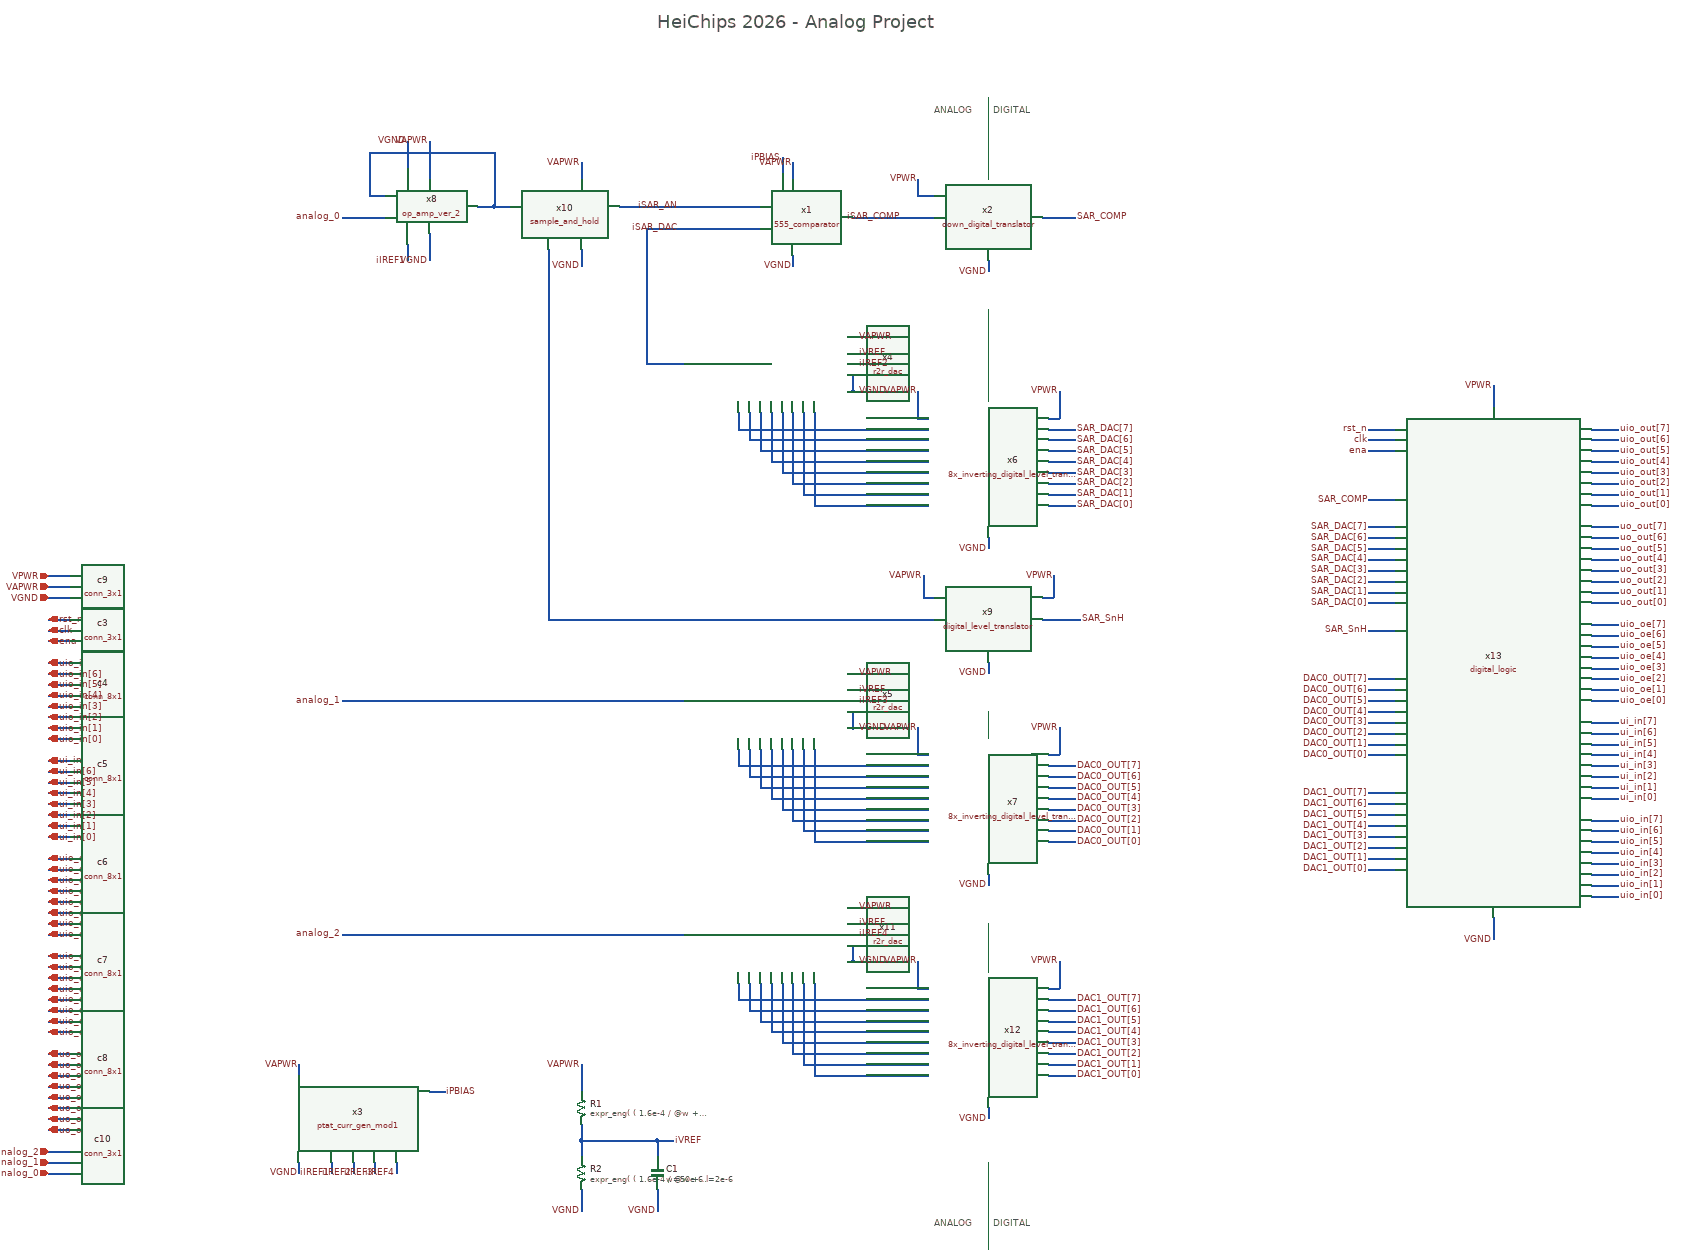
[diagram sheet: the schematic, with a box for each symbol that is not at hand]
v {xschem version=3.4.8RC file_version=1.3}
G {}
K {}
V {}
S {}
F {}
E {}
L 4 1890 -2240 1890 -2090 {fill = false
dash = 16}
L 4 1890 -1850 1890 -1680 {fill = false
dash = 16}
L 4 1890 -1110 1890 -1060 {fill = false
dash = 16}
L 4 1890 -720 1890 -630 {fill = false
dash = 16}
L 4 1890 -280 1890 -30 {fill = false
dash = 16}
T {HeiChips 2026 - Analog Project} 1280 -2390 0 0 1 1 {}
T {ANALOG} 1790 -2230 0 0 0.4 0.4 {}
T {DIGITAL} 1900 -2230 0 0 0.4 0.4 {}
T {ANALOG} 1790 -180 0 0 0.4 0.4 {}
T {DIGITAL} 1900 -180 0 0 0.4 0.4 {}
N 620 -460 620 -440 {lab=VAPWR}
N 1530 -2120 1530 -2090 {lab=VAPWR}
N 620 -280 620 -260 {lab=VGND}
N 1530 -1950 1530 -1930 {lab=VGND}
N 1890 -1940 1890 -1920 {lab=VGND}
N 1760 -2060 1790 -2060 {lab=VPWR}
N 1760 -2090 1760 -2060 {lab=VPWR}
N 2020 -1700 2020 -1650 {lab=VPWR}
N 2000 -1650 2020 -1650 {lab=VPWR}
N 2020 -1080 2020 -1030 {lab=VPWR}
N 2000 -1030 2020 -1030 {lab=VPWR}
N 1760 -1650 1780 -1650 {lab=VAPWR}
N 1760 -1700 1760 -1650 {lab=VAPWR}
N 1760 -1030 1780 -1030 {lab=VAPWR}
N 1760 -1080 1760 -1030 {lab=VAPWR}
N 1890 -810 1890 -790 {lab=VGND}
N 1890 -1430 1890 -1410 {lab=VGND}
N 1430 -1630 1780 -1630 {lab=#net1}
N 1430 -1660 1430 -1630 {lab=#net1}
N 1450 -1610 1780 -1610 {lab=#net2}
N 1450 -1660 1450 -1610 {lab=#net2}
N 1470 -1590 1780 -1590 {lab=#net3}
N 1470 -1660 1470 -1590 {lab=#net3}
N 1490 -1570 1780 -1570 {lab=#net4}
N 1490 -1660 1490 -1570 {lab=#net4}
N 1510 -1550 1780 -1550 {lab=#net5}
N 1510 -1660 1510 -1550 {lab=#net5}
N 1530 -1530 1780 -1530 {lab=#net6}
N 1530 -1660 1530 -1530 {lab=#net6}
N 1550 -1510 1780 -1510 {lab=#net7}
N 1550 -1660 1550 -1510 {lab=#net7}
N 1570 -1490 1780 -1490 {lab=#net8}
N 1570 -1660 1570 -1490 {lab=#net8}
N 1430 -1010 1780 -1010 {lab=#net9}
N 1430 -1040 1430 -1010 {lab=#net9}
N 1450 -990 1780 -990 {lab=#net10}
N 1450 -1040 1450 -990 {lab=#net10}
N 1470 -970 1780 -970 {lab=#net11}
N 1470 -1040 1470 -970 {lab=#net11}
N 1490 -950 1780 -950 {lab=#net12}
N 1490 -1040 1490 -950 {lab=#net12}
N 1510 -930 1780 -930 {lab=#net13}
N 1510 -1040 1510 -930 {lab=#net13}
N 1550 -890 1780 -890 {lab=#net14}
N 1550 -1040 1550 -890 {lab=#net14}
N 1530 -910 1780 -910 {lab=#net15}
N 1530 -1040 1530 -910 {lab=#net15}
N 1570 -870 1780 -870 {lab=#net16}
N 1570 -1040 1570 -870 {lab=#net16}
N 1640 -1700 1650 -1700 {lab=VGND}
N 1640 -1080 1650 -1080 {lab=VGND}
N 1630 -1180 1650 -1180 {lab=VAPWR}
N 1630 -1800 1650 -1800 {lab=VAPWR}
N 1630 -1730 1640 -1730 {lab=VGND}
N 1640 -1730 1640 -1700 {lab=VGND}
N 1630 -1700 1640 -1700 {lab=VGND}
N 1630 -1110 1640 -1110 {lab=VGND}
N 1640 -1110 1640 -1080 {lab=VGND}
N 1630 -1080 1640 -1080 {lab=VGND}
N 1640 -2020 1790 -2020 {lab=iSAR_COMP}
N 1260 -2000 1470 -2000 {lab=iSAR_DAC}
N 1260 -2000 1260 -1750 {lab=iSAR_DAC}
N 1260 -1750 1330 -1750 {lab=iSAR_DAC}
N 750 -2060 780 -2060 {lab=#net17}
N 750 -2140 750 -2060 {lab=#net17}
N 750 -2140 980 -2140 {lab=#net17}
N 950 -2040 980 -2040 {lab=#net17}
N 980 -2140 980 -2040 {lab=#net17}
N 860 -1990 860 -1940 {lab=VGND}
N 860 -2160 860 -2090 {lab=VAPWR}
N 820 -2160 820 -2110 {lab=VGND}
N 760 -280 760 -260 {lab=iIREF3}
N 720 -280 720 -260 {lab=iIREF2}
N 680 -280 680 -260 {lab=iIREF1}
N 1630 -1130 1650 -1130 {lab=iIREF3}
N 1630 -1750 1650 -1750 {lab=iIREF2}
N 820 -1970 820 -1940 {lab=iIREF1}
N 1140 -350 1140 -320 {lab=iVREF}
N 1140 -320 1280 -320 {lab=iVREF}
N 1280 -320 1280 -290 {lab=iVREF}
N 1140 -320 1140 -290 {lab=iVREF}
N 1280 -320 1310 -320 {lab=iVREF}
N 1140 -460 1140 -410 {lab=VAPWR}
N 1140 -230 1140 -190 {lab=VGND}
N 1630 -1770 1650 -1770 {lab=iVREF}
N 1630 -1150 1650 -1150 {lab=iVREF}
N 700 -2020 780 -2020 {lab=analog_0}
N 860 -410 890 -410 {lab=iPBIAS}
N 1510 -2130 1510 -2100 {lab=iPBIAS}
N 1770 -1320 1790 -1320 {lab=VAPWR}
N 1770 -1360 1770 -1320 {lab=VAPWR}
N 1990 -1320 2010 -1320 {lab=VPWR}
N 2010 -1360 2010 -1320 {lab=VPWR}
N 1890 -1200 1890 -1180 {lab=VGND}
N 1080 -1280 1790 -1280 {lab=#net18}
N 2000 -870 2050 -870 {lab=DAC0_OUT[0]}
N 2000 -890 2050 -890 {lab=DAC0_OUT[1]}
N 2000 -910 2050 -910 {lab=DAC0_OUT[2]}
N 2000 -930 2050 -930 {lab=DAC0_OUT[3]}
N 2000 -970 2050 -970 {lab=DAC0_OUT[5]}
N 2000 -950 2050 -950 {lab=DAC0_OUT[4]}
N 2000 -990 2050 -990 {lab=DAC0_OUT[6]}
N 2000 -1010 2050 -1010 {lab=DAC0_OUT[7]}
N 2000 -1490 2050 -1490 {lab=SAR_DAC[0]}
N 2000 -1510 2050 -1510 {lab=SAR_DAC[1]}
N 2000 -1530 2050 -1530 {lab=SAR_DAC[2]}
N 2000 -1550 2050 -1550 {lab=SAR_DAC[3]}
N 2000 -1570 2050 -1570 {lab=SAR_DAC[4]}
N 2000 -1590 2050 -1590 {lab=SAR_DAC[5]}
N 2000 -1610 2050 -1610 {lab=SAR_DAC[6]}
N 2000 -1630 2050 -1630 {lab=SAR_DAC[7]}
N 1990 -2020 2050 -2020 {lab=SAR_COMP}
N 1990 -1280 2060 -1280 {lab=SAR_SnH}
N 1280 -230 1280 -190 {lab=VGND}
N 160 -1260 200 -1260 {lab=clk}
N 160 -1240 200 -1240 {lab=ena}
N 160 -1280 200 -1280 {lab=rst_n}
N 160 -1200 200 -1200 {lab=uio_in[7]}
N 160 -1180 200 -1180 {lab=uio_in[6]}
N 160 -1160 200 -1160 {lab=uio_in[5]}
N 160 -1140 200 -1140 {lab=uio_in[4]}
N 160 -1120 200 -1120 {lab=uio_in[3]}
N 160 -1100 200 -1100 {lab=uio_in[2]}
N 160 -1080 200 -1080 {lab=uio_in[1]}
N 160 -1060 200 -1060 {lab=uio_in[0]}
N 160 -1020 200 -1020 {lab=ui_in[7]}
N 160 -1000 200 -1000 {lab=ui_in[6]}
N 160 -980 200 -980 {lab=ui_in[5]}
N 160 -960 200 -960 {lab=ui_in[4]}
N 160 -940 200 -940 {lab=ui_in[3]}
N 160 -920 200 -920 {lab=ui_in[2]}
N 160 -900 200 -900 {lab=ui_in[1]}
N 160 -880 200 -880 {lab=ui_in[0]}
N 160 -840 200 -840 {lab=uio_oe[7]}
N 160 -820 200 -820 {lab=uio_oe[6]}
N 160 -800 200 -800 {lab=uio_oe[5]}
N 160 -780 200 -780 {lab=uio_oe[4]}
N 160 -760 200 -760 {lab=uio_oe[3]}
N 160 -740 200 -740 {lab=uio_oe[2]}
N 160 -720 200 -720 {lab=uio_oe[1]}
N 160 -700 200 -700 {lab=uio_oe[0]}
N 160 -660 200 -660 {lab=uio_out[7]}
N 160 -640 200 -640 {lab=uio_out[6]}
N 160 -620 200 -620 {lab=uio_out[5]}
N 160 -600 200 -600 {lab=uio_out[4]}
N 160 -580 200 -580 {lab=uio_out[3]}
N 160 -560 200 -560 {lab=uio_out[2]}
N 160 -540 200 -540 {lab=uio_out[1]}
N 160 -520 200 -520 {lab=uio_out[0]}
N 160 -480 200 -480 {lab=uo_out[7]}
N 160 -460 200 -460 {lab=uo_out[6]}
N 160 -440 200 -440 {lab=uo_out[5]}
N 160 -420 200 -420 {lab=uo_out[4]}
N 160 -400 200 -400 {lab=uo_out[3]}
N 160 -380 200 -380 {lab=uo_out[2]}
N 160 -360 200 -360 {lab=uo_out[1]}
N 160 -340 200 -340 {lab=uo_out[0]}
N 160 -1340 200 -1340 {lab=VAPWR}
N 160 -1320 200 -1320 {lab=VGND}
N 160 -1360 200 -1360 {lab=VPWR}
N 160 -300 200 -300 {lab=analog_2}
N 160 -280 200 -280 {lab=analog_1}
N 160 -260 200 -260 {lab=analog_0}
N 980 -2040 1010 -2040 {lab=#net17}
N 1210 -2040 1470 -2040 {lab=iSAR_AN}
N 1080 -1960 1080 -1280 {lab=#net18}
N 1140 -1960 1140 -1930 {lab=VGND}
N 1140 -2120 1140 -2090 {lab=VAPWR}
N 2020 -650 2020 -600 {lab=VPWR}
N 2000 -600 2020 -600 {lab=VPWR}
N 1760 -600 1780 -600 {lab=VAPWR}
N 1760 -650 1760 -600 {lab=VAPWR}
N 1890 -380 1890 -360 {lab=VGND}
N 1430 -580 1780 -580 {lab=#net19}
N 1430 -610 1430 -580 {lab=#net19}
N 1450 -560 1780 -560 {lab=#net20}
N 1450 -610 1450 -560 {lab=#net20}
N 1470 -540 1780 -540 {lab=#net21}
N 1470 -610 1470 -540 {lab=#net21}
N 1490 -520 1780 -520 {lab=#net22}
N 1490 -610 1490 -520 {lab=#net22}
N 1510 -500 1780 -500 {lab=#net23}
N 1510 -610 1510 -500 {lab=#net23}
N 1550 -460 1780 -460 {lab=#net24}
N 1550 -610 1550 -460 {lab=#net24}
N 1530 -480 1780 -480 {lab=#net25}
N 1530 -610 1530 -480 {lab=#net25}
N 1570 -440 1780 -440 {lab=#net26}
N 1570 -610 1570 -440 {lab=#net26}
N 1640 -650 1650 -650 {lab=VGND}
N 1630 -750 1650 -750 {lab=VAPWR}
N 1630 -680 1640 -680 {lab=VGND}
N 1640 -680 1640 -650 {lab=VGND}
N 1630 -650 1640 -650 {lab=VGND}
N 1630 -700 1650 -700 {lab=iIREF4}
N 1630 -720 1650 -720 {lab=iVREF}
N 800 -280 800 -260 {lab=iIREF3}
N 700 -700 1330 -700 {lab=analog_2}
N 700 -1130 1330 -1130 {lab=analog_1}
N 2000 -440 2050 -440 {lab=DAC1_OUT[0]}
N 2000 -460 2050 -460 {lab=DAC1_OUT[1]}
N 2000 -480 2050 -480 {lab=DAC1_OUT[2]}
N 2000 -500 2050 -500 {lab=DAC1_OUT[3]}
N 2000 -540 2050 -540 {lab=DAC1_OUT[5]}
N 2000 -520 2050 -520 {lab=DAC1_OUT[4]}
N 2000 -560 2050 -560 {lab=DAC1_OUT[6]}
N 2000 -580 2050 -580 {lab=DAC1_OUT[7]}
N 2590 -820 2640 -820 {lab=DAC1_OUT[0]}
N 2590 -840 2640 -840 {lab=DAC1_OUT[1]}
N 2590 -860 2640 -860 {lab=DAC1_OUT[2]}
N 2590 -880 2640 -880 {lab=DAC1_OUT[3]}
N 2590 -920 2640 -920 {lab=DAC1_OUT[5]}
N 2590 -900 2640 -900 {lab=DAC1_OUT[4]}
N 2590 -940 2640 -940 {lab=DAC1_OUT[6]}
N 2590 -960 2640 -960 {lab=DAC1_OUT[7]}
N 2590 -1030 2640 -1030 {lab=DAC0_OUT[0]}
N 2590 -1050 2640 -1050 {lab=DAC0_OUT[1]}
N 2590 -1070 2640 -1070 {lab=DAC0_OUT[2]}
N 2590 -1090 2640 -1090 {lab=DAC0_OUT[3]}
N 2590 -1130 2640 -1130 {lab=DAC0_OUT[5]}
N 2590 -1110 2640 -1110 {lab=DAC0_OUT[4]}
N 2590 -1150 2640 -1150 {lab=DAC0_OUT[6]}
N 2590 -1170 2640 -1170 {lab=DAC0_OUT[7]}
N 2590 -1260 2640 -1260 {lab=SAR_SnH}
N 2590 -1310 2640 -1310 {lab=SAR_DAC[0]}
N 2590 -1330 2640 -1330 {lab=SAR_DAC[1]}
N 2590 -1350 2640 -1350 {lab=SAR_DAC[2]}
N 2590 -1370 2640 -1370 {lab=SAR_DAC[3]}
N 2590 -1390 2640 -1390 {lab=SAR_DAC[4]}
N 2590 -1410 2640 -1410 {lab=SAR_DAC[5]}
N 2590 -1430 2640 -1430 {lab=SAR_DAC[6]}
N 2590 -1450 2640 -1450 {lab=SAR_DAC[7]}
N 2590 -1500 2640 -1500 {lab=SAR_COMP}
N 2590 -1630 2640 -1630 {lab=rst_n}
N 2590 -1610 2640 -1610 {lab=clk}
N 2590 -1590 2640 -1590 {lab=ena}
N 2820 -730 2820 -690 {lab=VGND}
N 2820 -1710 2820 -1670 {lab=VPWR}
N 3000 -1490 3050 -1490 {lab=SAR_DAC[0]}
N 3000 -1510 3050 -1510 {lab=SAR_DAC[1]}
N 3000 -1530 3050 -1530 {lab=SAR_DAC[2]}
N 3000 -1550 3050 -1550 {lab=SAR_DAC[3]}
N 3000 -1570 3050 -1570 {lab=SAR_DAC[4]}
N 3000 -1590 3050 -1590 {lab=SAR_DAC[5]}
N 3000 -1610 3050 -1610 {lab=SAR_DAC[6]}
N 3000 -1630 3050 -1630 {lab=SAR_DAC[7]}
N 3000 -1310 3050 -1310 {lab=SAR_DAC[0]}
N 3000 -1330 3050 -1330 {lab=SAR_DAC[1]}
N 3000 -1350 3050 -1350 {lab=SAR_DAC[2]}
N 3000 -1370 3050 -1370 {lab=SAR_DAC[3]}
N 3000 -1390 3050 -1390 {lab=SAR_DAC[4]}
N 3000 -1410 3050 -1410 {lab=SAR_DAC[5]}
N 3000 -1430 3050 -1430 {lab=SAR_DAC[6]}
N 3000 -1450 3050 -1450 {lab=SAR_DAC[7]}
N 3000 -1130 3050 -1130 {lab=SAR_DAC[0]}
N 3000 -1150 3050 -1150 {lab=SAR_DAC[1]}
N 3000 -1170 3050 -1170 {lab=SAR_DAC[2]}
N 3000 -1190 3050 -1190 {lab=SAR_DAC[3]}
N 3000 -1210 3050 -1210 {lab=SAR_DAC[4]}
N 3000 -1230 3050 -1230 {lab=SAR_DAC[5]}
N 3000 -1250 3050 -1250 {lab=SAR_DAC[6]}
N 3000 -1270 3050 -1270 {lab=SAR_DAC[7]}
N 3000 -950 3050 -950 {lab=SAR_DAC[0]}
N 3000 -970 3050 -970 {lab=SAR_DAC[1]}
N 3000 -990 3050 -990 {lab=SAR_DAC[2]}
N 3000 -1010 3050 -1010 {lab=SAR_DAC[3]}
N 3000 -1030 3050 -1030 {lab=SAR_DAC[4]}
N 3000 -1050 3050 -1050 {lab=SAR_DAC[5]}
N 3000 -1070 3050 -1070 {lab=SAR_DAC[6]}
N 3000 -1090 3050 -1090 {lab=SAR_DAC[7]}
N 3000 -770 3050 -770 {lab=SAR_DAC[0]}
N 3000 -790 3050 -790 {lab=SAR_DAC[1]}
N 3000 -810 3050 -810 {lab=SAR_DAC[2]}
N 3000 -830 3050 -830 {lab=SAR_DAC[3]}
N 3000 -850 3050 -850 {lab=SAR_DAC[4]}
N 3000 -870 3050 -870 {lab=SAR_DAC[5]}
N 3000 -890 3050 -890 {lab=SAR_DAC[6]}
N 3000 -910 3050 -910 {lab=SAR_DAC[7]}
C {title-2.sym} 0 0 0 0 {name=l1 author="B. L., G. B., T. M., P. G." rev=1.0 lock=true}
C {555_comparator.sym} 1490 -2020 0 0 {name=x1}
C {down_digital_translator.sym} 1810 -1960 0 0 {name=x2}
C {ptat_curr_gen_mod1.sym} 590 -300 0 0 {name=x3}
C {r2r_dac.sym} 1690 -1590 0 1 {name=x4}
C {r2r_dac.sym} 1690 -970 0 1 {name=x5}
C {8x_inverting_digital_level_translator.sym} 1980 -1450 0 1 {name=x6}
C {8x_inverting_digital_level_translator.sym} 1980 -830 0 1 {name=x7}
C {lab_pin.sym} 620 -460 1 0 {name=p1 sig_type=std_logic lab=VAPWR
}
C {lab_pin.sym} 1530 -2120 1 0 {name=p2 sig_type=std_logic lab=VAPWR
}
C {lab_pin.sym} 620 -260 3 0 {name=p5 sig_type=std_logic lab=VGND
}
C {lab_pin.sym} 1530 -1930 3 0 {name=p6 sig_type=std_logic lab=VGND
}
C {lab_pin.sym} 1890 -1920 3 0 {name=p7 sig_type=std_logic lab=VGND
}
C {lab_pin.sym} 1760 -2090 1 0 {name=p10 sig_type=std_logic lab=VPWR
}
C {lab_pin.sym} 2020 -1700 1 0 {name=p11 sig_type=std_logic lab=VPWR
}
C {lab_pin.sym} 2020 -1080 1 0 {name=p19 sig_type=std_logic lab=VPWR
}
C {lab_pin.sym} 1760 -1700 1 0 {name=p20 sig_type=std_logic lab=VAPWR
}
C {lab_pin.sym} 1760 -1080 1 0 {name=p21 sig_type=std_logic lab=VAPWR
}
C {lab_pin.sym} 1890 -1410 3 0 {name=p22 sig_type=std_logic lab=VGND
}
C {lab_pin.sym} 1890 -790 3 0 {name=p23 sig_type=std_logic lab=VGND
}
C {lab_pin.sym} 1650 -1800 2 0 {name=p24 sig_type=std_logic lab=VAPWR
}
C {lab_pin.sym} 1650 -1180 2 0 {name=p67 sig_type=std_logic lab=VAPWR
}
C {lab_pin.sym} 1650 -1080 2 0 {name=p68 sig_type=std_logic lab=VGND
}
C {lab_pin.sym} 1650 -1700 2 0 {name=p69 sig_type=std_logic lab=VGND
}
C {lab_pin.sym} 890 -410 2 0 {name=p70 sig_type=std_logic lab=iPBIAS
}
C {op_amp_ver_2.sym} 850 -2040 0 0 {name=x8}
C {lab_pin.sym} 860 -2160 1 0 {name=p71 sig_type=std_logic lab=VAPWR
}
C {lab_pin.sym} 860 -1940 3 0 {name=p72 sig_type=std_logic lab=VGND
}
C {lab_pin.sym} 820 -2160 1 0 {name=p73 sig_type=std_logic lab=VGND
}
C {lab_pin.sym} 680 -260 3 0 {name=p74 sig_type=std_logic lab=iIREF1
}
C {lab_pin.sym} 720 -260 3 0 {name=p75 sig_type=std_logic lab=iIREF2

}
C {lab_pin.sym} 760 -260 3 0 {name=p76 sig_type=std_logic lab=iIREF3
}
C {lab_pin.sym} 820 -1940 3 0 {name=p77 sig_type=std_logic lab=iIREF1
}
C {lab_pin.sym} 1650 -1750 2 0 {name=p78 sig_type=std_logic lab=iIREF2

}
C {lab_pin.sym} 1650 -1130 2 0 {name=p79 sig_type=std_logic lab=iIREF3
}
C {sg13cmos5l_pr/rhigh.sym} 1140 -380 0 0 {name=R1
w=0.5e-6
l=50e-6
model=rhigh
body=VGND
spiceprefix=X
b=0
 m=1
  mm_ok=1
value="expr_eng(  ( 1.6e-4 / @w + 1360.0 * ( (@b + 1)* @l + ( 1.081*( @w - 0.04e-6 ) + 0.18e-6 )*@b ) / ( @w - 0.04e-6 ) ) / @m  )"
}
C {sg13cmos5l_pr/rhigh.sym} 1140 -260 0 0 {name=R2
w=0.5e-6
l=50e-6
model=rhigh
body=VGND
spiceprefix=X
b=0
 m=1
  mm_ok=1
value="expr_eng(  ( 1.6e-4 / @w + 1360.0 * ( (@b + 1)* @l + ( 1.081*( @w - 0.04e-6 ) + 0.18e-6 )*@b ) / ( @w - 0.04e-6 ) ) / @m  )"
}
C {sg13cmos5l_pr/cap_cmomi.sym} 1280 -260 0 0 {name=C1
model=cap_cmomi
w=50e-6
l=2e-6
mmin=2
mmax=3
feed=double
subblock=0
m=1
mm_ok=1
spiceprefix=X
}
C {lab_pin.sym} 1140 -460 1 0 {name=p80 sig_type=std_logic lab=VAPWR
}
C {lab_pin.sym} 1140 -190 3 0 {name=p81 sig_type=std_logic lab=VGND
}
C {lab_pin.sym} 1310 -320 2 0 {name=p82 sig_type=std_logic lab=iVREF
}
C {lab_pin.sym} 1650 -1150 2 0 {name=p83 sig_type=std_logic lab=iVREF
}
C {lab_pin.sym} 1650 -1770 2 0 {name=p84 sig_type=std_logic lab=iVREF
}
C {lab_pin.sym} 1510 -2130 1 0 {name=p87 sig_type=std_logic lab=iPBIAS
}
C {digital_level_translator.sym} 1970 -1220 0 1 {name=x9}
C {lab_pin.sym} 1770 -1360 1 0 {name=p88 sig_type=std_logic lab=VAPWR
}
C {lab_pin.sym} 2010 -1360 1 0 {name=p89 sig_type=std_logic lab=VPWR
}
C {lab_pin.sym} 1890 -1180 3 0 {name=p90 sig_type=std_logic lab=VGND
}
C {lab_wire.sym} 1320 -2000 0 0 {name=p91 sig_type=std_logic lab=iSAR_DAC}
C {lab_wire.sym} 1730 -2020 0 0 {name=p92 sig_type=std_logic lab=iSAR_COMP}
C {lab_wire.sym} 1320 -2040 0 0 {name=p93 sig_type=std_logic lab=iSAR_AN}
C {lab_pin.sym} 2050 -870 0 1 {name=p94 lab=DAC0_OUT[0]
}
C {lab_pin.sym} 2050 -890 0 1 {name=p95 lab=DAC0_OUT[1]
}
C {lab_pin.sym} 2050 -910 0 1 {name=p96 lab=DAC0_OUT[2]
}
C {lab_pin.sym} 2050 -930 0 1 {name=p97 lab=DAC0_OUT[3]
}
C {lab_pin.sym} 2050 -950 0 1 {name=p98 lab=DAC0_OUT[4]
}
C {lab_pin.sym} 2050 -970 0 1 {name=p99 lab=DAC0_OUT[5]
}
C {lab_pin.sym} 2050 -990 0 1 {name=p100 lab=DAC0_OUT[6]
}
C {lab_pin.sym} 2050 -1010 0 1 {name=p101 lab=DAC0_OUT[7]
}
C {lab_pin.sym} 2050 -1490 0 1 {name=p102 lab=SAR_DAC[0]
}
C {lab_pin.sym} 2050 -1510 0 1 {name=p103 lab=SAR_DAC[1]
}
C {lab_pin.sym} 2050 -1530 0 1 {name=p104 lab=SAR_DAC[2]
}
C {lab_pin.sym} 2050 -1550 0 1 {name=p105 lab=SAR_DAC[3]
}
C {lab_pin.sym} 2050 -1570 0 1 {name=p106 lab=SAR_DAC[4]
}
C {lab_pin.sym} 2050 -1590 0 1 {name=p107 lab=SAR_DAC[5]
}
C {lab_pin.sym} 2050 -1610 0 1 {name=p108 lab=SAR_DAC[6]
}
C {lab_pin.sym} 2050 -1630 0 1 {name=p109 lab=SAR_DAC[7]
}
C {lab_pin.sym} 2050 -2020 2 0 {name=p110 lab=SAR_COMP}
C {lab_pin.sym} 2060 -1280 0 1 {name=p111 lab=SAR_SnH
}
C {lab_pin.sym} 1280 -190 3 0 {name=p8 sig_type=std_logic lab=VGND
}
C {devices/ipin.sym} 160 -1280 2 1 {name=p30 lab=rst_n}
C {devices/ipin.sym} 160 -1260 2 1 {name=p31 lab=clk}
C {devices/ipin.sym} 160 -1240 2 1 {name=p32 lab=ena}
C {devices/ipin.sym} 160 -1200 2 1 {name=p33 lab=uio_in[7]}
C {conn_3x1.sym} 220 -1260 0 1 {name=c3 footprint=connector(3,1)}
C {conn_8x1.sym} 220 -1180 0 1 {name=c4 footprint=connector(8,1)}
C {devices/ipin.sym} 160 -1020 2 1 {name=p3 lab=ui_in[7]}
C {conn_8x1.sym} 220 -1000 0 1 {name=c5 footprint=connector(8,1)}
C {devices/opin.sym} 160 -840 2 0 {name=p18 lab=uio_oe[7]}
C {devices/opin.sym} 160 -820 2 0 {name=p27 lab=uio_oe[6]}
C {devices/opin.sym} 160 -800 2 0 {name=p28 lab=uio_oe[5]}
C {devices/opin.sym} 160 -780 2 0 {name=p29 lab=uio_oe[4]}
C {devices/opin.sym} 160 -760 2 0 {name=p41 lab=uio_oe[3]}
C {devices/opin.sym} 160 -740 2 0 {name=p42 lab=uio_oe[2]}
C {devices/opin.sym} 160 -720 2 0 {name=p43 lab=uio_oe[1]}
C {devices/opin.sym} 160 -700 2 0 {name=p44 lab=uio_oe[0]}
C {conn_8x1.sym} 220 -820 0 1 {name=c6 footprint=connector(8,1)}
C {devices/opin.sym} 160 -660 2 0 {name=p45 lab=uio_out[7]}
C {devices/opin.sym} 160 -640 2 0 {name=p46 lab=uio_out[6]}
C {devices/opin.sym} 160 -620 2 0 {name=p47 lab=uio_out[5]}
C {devices/opin.sym} 160 -600 2 0 {name=p48 lab=uio_out[4]}
C {devices/opin.sym} 160 -580 2 0 {name=p49 lab=uio_out[3]}
C {devices/opin.sym} 160 -560 2 0 {name=p50 lab=uio_out[2]}
C {devices/opin.sym} 160 -540 2 0 {name=p51 lab=uio_out[1]}
C {devices/opin.sym} 160 -520 2 0 {name=p52 lab=uio_out[0]}
C {conn_8x1.sym} 220 -640 0 1 {name=c7 footprint=connector(8,1)}
C {devices/opin.sym} 160 -480 2 0 {name=p53 lab=uo_out[7]}
C {devices/opin.sym} 160 -460 2 0 {name=p54 lab=uo_out[6]}
C {devices/opin.sym} 160 -440 2 0 {name=p55 lab=uo_out[5]}
C {devices/opin.sym} 160 -420 2 0 {name=p56 lab=uo_out[4]}
C {devices/opin.sym} 160 -400 2 0 {name=p57 lab=uo_out[3]}
C {devices/opin.sym} 160 -380 2 0 {name=p58 lab=uo_out[2]}
C {devices/opin.sym} 160 -360 2 0 {name=p59 lab=uo_out[1]}
C {devices/opin.sym} 160 -340 2 0 {name=p60 lab=uo_out[0]}
C {conn_8x1.sym} 220 -460 0 1 {name=c8 footprint=connector(8,1)}
C {conn_3x1.sym} 220 -1340 0 1 {name=c9 footprint=connector(3,1)}
C {devices/iopin.sym} 160 -1360 2 0 {name=p4 lab=VPWR}
C {devices/iopin.sym} 160 -1320 2 0 {name=p9 lab=VGND}
C {devices/iopin.sym} 160 -1340 2 0 {name=p12 lab=VAPWR}
C {devices/ipin.sym} 160 -1000 2 1 {name=p13 lab=ui_in[6]}
C {devices/ipin.sym} 160 -980 2 1 {name=p14 lab=ui_in[5]}
C {devices/ipin.sym} 160 -960 2 1 {name=p15 lab=ui_in[4]}
C {devices/ipin.sym} 160 -940 2 1 {name=p16 lab=ui_in[3]}
C {devices/ipin.sym} 160 -920 2 1 {name=p17 lab=ui_in[2]}
C {devices/ipin.sym} 160 -900 2 1 {name=p25 lab=ui_in[1]}
C {devices/ipin.sym} 160 -880 2 1 {name=p26 lab=ui_in[0]}
C {devices/ipin.sym} 160 -1180 2 1 {name=p34 lab=uio_in[6]}
C {devices/ipin.sym} 160 -1160 2 1 {name=p35 lab=uio_in[5]}
C {devices/ipin.sym} 160 -1140 2 1 {name=p36 lab=uio_in[4]}
C {devices/ipin.sym} 160 -1120 2 1 {name=p37 lab=uio_in[3]}
C {devices/ipin.sym} 160 -1100 2 1 {name=p38 lab=uio_in[2]}
C {devices/ipin.sym} 160 -1080 2 1 {name=p39 lab=uio_in[1]}
C {devices/ipin.sym} 160 -1060 2 1 {name=p40 lab=uio_in[0]}
C {conn_3x1.sym} 220 -280 0 1 {name=c10 footprint=connector(3,1)}
C {devices/iopin.sym} 160 -300 2 0 {name=p65 lab=analog_2}
C {devices/iopin.sym} 160 -280 2 0 {name=p66 lab=analog_1}
C {devices/iopin.sym} 160 -260 2 0 {name=p115 lab=analog_0}
C {sample_and_hold.sym} 1060 -2010 0 0 {name=x10}
C {lab_pin.sym} 1140 -2120 1 0 {name=p61 sig_type=std_logic lab=VAPWR
}
C {lab_pin.sym} 1140 -1930 3 0 {name=p62 sig_type=std_logic lab=VGND
}
C {r2r_dac.sym} 1690 -540 0 1 {name=x11}
C {8x_inverting_digital_level_translator.sym} 1980 -400 0 1 {name=x12}
C {lab_pin.sym} 2020 -650 1 0 {name=p63 sig_type=std_logic lab=VPWR
}
C {lab_pin.sym} 1760 -650 1 0 {name=p64 sig_type=std_logic lab=VAPWR
}
C {lab_pin.sym} 1890 -360 3 0 {name=p112 sig_type=std_logic lab=VGND
}
C {lab_pin.sym} 1650 -750 2 0 {name=p113 sig_type=std_logic lab=VAPWR
}
C {lab_pin.sym} 1650 -650 2 0 {name=p114 sig_type=std_logic lab=VGND
}
C {lab_pin.sym} 1650 -700 2 0 {name=p116 sig_type=std_logic lab=iIREF4}
C {lab_pin.sym} 1650 -720 2 0 {name=p117 sig_type=std_logic lab=iVREF
}
C {lab_pin.sym} 700 -2020 0 0 {name=p119 sig_type=std_logic lab=analog_0
}
C {lab_pin.sym} 700 -1130 0 0 {name=p85 sig_type=std_logic lab=analog_1}
C {lab_pin.sym} 700 -700 0 0 {name=p86 sig_type=std_logic lab=analog_2}
C {lab_pin.sym} 800 -260 3 0 {name=p118 sig_type=std_logic lab=iIREF4
}
C {lab_pin.sym} 2050 -440 0 1 {name=p120 lab=DAC1_OUT[0]
}
C {lab_pin.sym} 2050 -460 0 1 {name=p121 lab=DAC1_OUT[1]
}
C {lab_pin.sym} 2050 -480 0 1 {name=p122 lab=DAC1_OUT[2]
}
C {lab_pin.sym} 2050 -500 0 1 {name=p123 lab=DAC1_OUT[3]
}
C {lab_pin.sym} 2050 -520 0 1 {name=p124 lab=DAC1_OUT[4]
}
C {lab_pin.sym} 2050 -540 0 1 {name=p125 lab=DAC1_OUT[5]
}
C {lab_pin.sym} 2050 -560 0 1 {name=p126 lab=DAC1_OUT[6]
}
C {lab_pin.sym} 2050 -580 0 1 {name=p127 lab=DAC1_OUT[7]
}
C {digital_logic.sym} 2820 -1330 0 0 {name=x13}
C {lab_pin.sym} 2590 -820 0 0 {name=p128 lab=DAC1_OUT[0]
}
C {lab_pin.sym} 2590 -840 0 0 {name=p129 lab=DAC1_OUT[1]
}
C {lab_pin.sym} 2590 -860 0 0 {name=p130 lab=DAC1_OUT[2]
}
C {lab_pin.sym} 2590 -880 0 0 {name=p131 lab=DAC1_OUT[3]
}
C {lab_pin.sym} 2590 -900 0 0 {name=p132 lab=DAC1_OUT[4]
}
C {lab_pin.sym} 2590 -920 0 0 {name=p133 lab=DAC1_OUT[5]
}
C {lab_pin.sym} 2590 -940 0 0 {name=p134 lab=DAC1_OUT[6]
}
C {lab_pin.sym} 2590 -960 0 0 {name=p135 lab=DAC1_OUT[7]
}
C {lab_pin.sym} 2590 -1030 0 0 {name=p136 lab=DAC0_OUT[0]
}
C {lab_pin.sym} 2590 -1050 0 0 {name=p137 lab=DAC0_OUT[1]
}
C {lab_pin.sym} 2590 -1070 0 0 {name=p138 lab=DAC0_OUT[2]
}
C {lab_pin.sym} 2590 -1090 0 0 {name=p139 lab=DAC0_OUT[3]
}
C {lab_pin.sym} 2590 -1110 0 0 {name=p140 lab=DAC0_OUT[4]
}
C {lab_pin.sym} 2590 -1130 0 0 {name=p141 lab=DAC0_OUT[5]
}
C {lab_pin.sym} 2590 -1150 0 0 {name=p142 lab=DAC0_OUT[6]
}
C {lab_pin.sym} 2590 -1170 0 0 {name=p143 lab=DAC0_OUT[7]
}
C {lab_pin.sym} 2590 -1260 0 0 {name=p144 lab=SAR_SnH
}
C {lab_pin.sym} 2590 -1310 0 0 {name=p145 lab=SAR_DAC[0]
}
C {lab_pin.sym} 2590 -1330 0 0 {name=p146 lab=SAR_DAC[1]
}
C {lab_pin.sym} 2590 -1350 0 0 {name=p147 lab=SAR_DAC[2]
}
C {lab_pin.sym} 2590 -1370 0 0 {name=p148 lab=SAR_DAC[3]
}
C {lab_pin.sym} 2590 -1390 0 0 {name=p149 lab=SAR_DAC[4]
}
C {lab_pin.sym} 2590 -1410 0 0 {name=p150 lab=SAR_DAC[5]
}
C {lab_pin.sym} 2590 -1430 0 0 {name=p151 lab=SAR_DAC[6]
}
C {lab_pin.sym} 2590 -1450 0 0 {name=p152 lab=SAR_DAC[7]
}
C {lab_pin.sym} 2590 -1500 2 1 {name=p153 lab=SAR_COMP}
C {lab_pin.sym} 2590 -1590 2 1 {name=p154 lab=ena}
C {lab_pin.sym} 2590 -1610 2 1 {name=p155 lab=clk}
C {lab_pin.sym} 2590 -1630 2 1 {name=p156 lab=rst_n}
C {lab_pin.sym} 2820 -690 3 0 {name=p157 sig_type=std_logic lab=VGND
}
C {lab_pin.sym} 2820 -1710 1 0 {name=p158 sig_type=std_logic lab=VPWR
}
C {lab_pin.sym} 3050 -1490 0 1 {name=p160 lab=uio_out[0]
}
C {lab_pin.sym} 3050 -1510 0 1 {name=p161 lab=uio_out[1]
}
C {lab_pin.sym} 3050 -1530 0 1 {name=p162 lab=uio_out[2]
}
C {lab_pin.sym} 3050 -1550 0 1 {name=p163 lab=uio_out[3]
}
C {lab_pin.sym} 3050 -1570 0 1 {name=p164 lab=uio_out[4]
}
C {lab_pin.sym} 3050 -1590 0 1 {name=p165 lab=uio_out[5]
}
C {lab_pin.sym} 3050 -1610 0 1 {name=p166 lab=uio_out[6]
}
C {lab_pin.sym} 3050 -1630 0 1 {name=p167 lab=uio_out[7]
}
C {lab_pin.sym} 3050 -1310 0 1 {name=p159 lab=uo_out[0]
}
C {lab_pin.sym} 3050 -1330 0 1 {name=p168 lab=uo_out[1]
}
C {lab_pin.sym} 3050 -1350 0 1 {name=p169 lab=uo_out[2]
}
C {lab_pin.sym} 3050 -1370 0 1 {name=p170 lab=uo_out[3]
}
C {lab_pin.sym} 3050 -1390 0 1 {name=p171 lab=uo_out[4]
}
C {lab_pin.sym} 3050 -1410 0 1 {name=p172 lab=uo_out[5]
}
C {lab_pin.sym} 3050 -1430 0 1 {name=p173 lab=uo_out[6]
}
C {lab_pin.sym} 3050 -1450 0 1 {name=p174 lab=uo_out[7]
}
C {lab_pin.sym} 3050 -1130 0 1 {name=p175 lab=uio_oe[0]
}
C {lab_pin.sym} 3050 -1150 0 1 {name=p176 lab=uio_oe[1]
}
C {lab_pin.sym} 3050 -1170 0 1 {name=p177 lab=uio_oe[2]
}
C {lab_pin.sym} 3050 -1190 0 1 {name=p178 lab=uio_oe[3]
}
C {lab_pin.sym} 3050 -1210 0 1 {name=p179 lab=uio_oe[4]
}
C {lab_pin.sym} 3050 -1230 0 1 {name=p180 lab=uio_oe[5]
}
C {lab_pin.sym} 3050 -1250 0 1 {name=p181 lab=uio_oe[6]
}
C {lab_pin.sym} 3050 -1270 0 1 {name=p182 lab=uio_oe[7]
}
C {lab_pin.sym} 3050 -950 0 1 {name=p183 lab=ui_in[0]
}
C {lab_pin.sym} 3050 -970 0 1 {name=p184 lab=ui_in[1]
}
C {lab_pin.sym} 3050 -990 0 1 {name=p185 lab=ui_in[2]
}
C {lab_pin.sym} 3050 -1010 0 1 {name=p186 lab=ui_in[3]
}
C {lab_pin.sym} 3050 -1030 0 1 {name=p187 lab=ui_in[4]
}
C {lab_pin.sym} 3050 -1050 0 1 {name=p188 lab=ui_in[5]
}
C {lab_pin.sym} 3050 -1070 0 1 {name=p189 lab=ui_in[6]
}
C {lab_pin.sym} 3050 -1090 0 1 {name=p190 lab=ui_in[7]
}
C {lab_pin.sym} 3050 -770 0 1 {name=p191 lab=uio_in[0]
}
C {lab_pin.sym} 3050 -790 0 1 {name=p192 lab=uio_in[1]
}
C {lab_pin.sym} 3050 -810 0 1 {name=p193 lab=uio_in[2]
}
C {lab_pin.sym} 3050 -830 0 1 {name=p194 lab=uio_in[3]
}
C {lab_pin.sym} 3050 -850 0 1 {name=p195 lab=uio_in[4]
}
C {lab_pin.sym} 3050 -870 0 1 {name=p196 lab=uio_in[5]
}
C {lab_pin.sym} 3050 -890 0 1 {name=p197 lab=uio_in[6]
}
C {lab_pin.sym} 3050 -910 0 1 {name=p198 lab=uio_in[7]
}
